VERSION 5.8 ;
BUSBITCHARS "[]" ;
DIVIDERCHAR "/" ;
UNITS
  DATABASE MICRONS 2000 ;
  TIME NANOSECONDS 1 ;
  CAPACITANCE PICOFARADS 1 ;
  RESISTANCE OHMS 1 ;
END UNITS
MANUFACTURINGGRID 0.005 ;
SITE unit
  SIZE 1.0 BY 1.0 ;
  CLASS CORE ;
  SYMMETRY Y ;
END unit
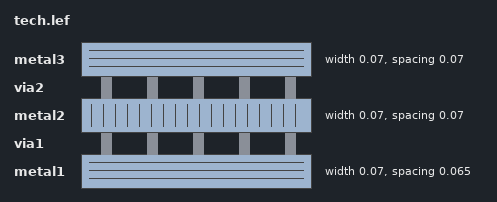
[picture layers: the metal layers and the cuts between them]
LAYER metal1
  TYPE ROUTING ;
  SPACING 0.065 ;
  WIDTH 0.07 ;
  DIRECTION HORIZONTAL ;
  RESISTANCE RPERSQ 5.0 ;
  CAPACITANCE CPERSQDIST 0.001 ;
END metal1
LAYER via1
  TYPE CUT ;
END via1
LAYER metal2
  TYPE ROUTING ;
  SPACING 0.07 ;
  WIDTH 0.07 ;
  DIRECTION VERTICAL ;
  RESISTANCE RPERSQ 5.0 ;
  CAPACITANCE CPERSQDIST 0.001 ;
END metal2
LAYER via2
  TYPE CUT ;
END via2
LAYER metal3
  TYPE ROUTING ;
  SPACING 0.07 ;
  WIDTH 0.07 ;
  DIRECTION HORIZONTAL ;
  RESISTANCE RPERSQ 5.0 ;
  CAPACITANCE CPERSQDIST 0.001 ;
END metal3
VIA via12 DEFAULT
  LAYER metal1 ;
    RECT -0.05 -0.05 0.05 0.05 ;
  LAYER via1 ;
    RECT -0.035 -0.035 0.035 0.035 ;
  LAYER metal2 ;
    RECT -0.05 -0.05 0.05 0.05 ;
END via12
VIA via23 DEFAULT
  LAYER metal2 ;
    RECT -0.05 -0.05 0.05 0.05 ;
  LAYER via2 ;
    RECT -0.035 -0.035 0.035 0.035 ;
  LAYER metal3 ;
    RECT -0.05 -0.05 0.05 0.05 ;
END via23
END LIBRARY
